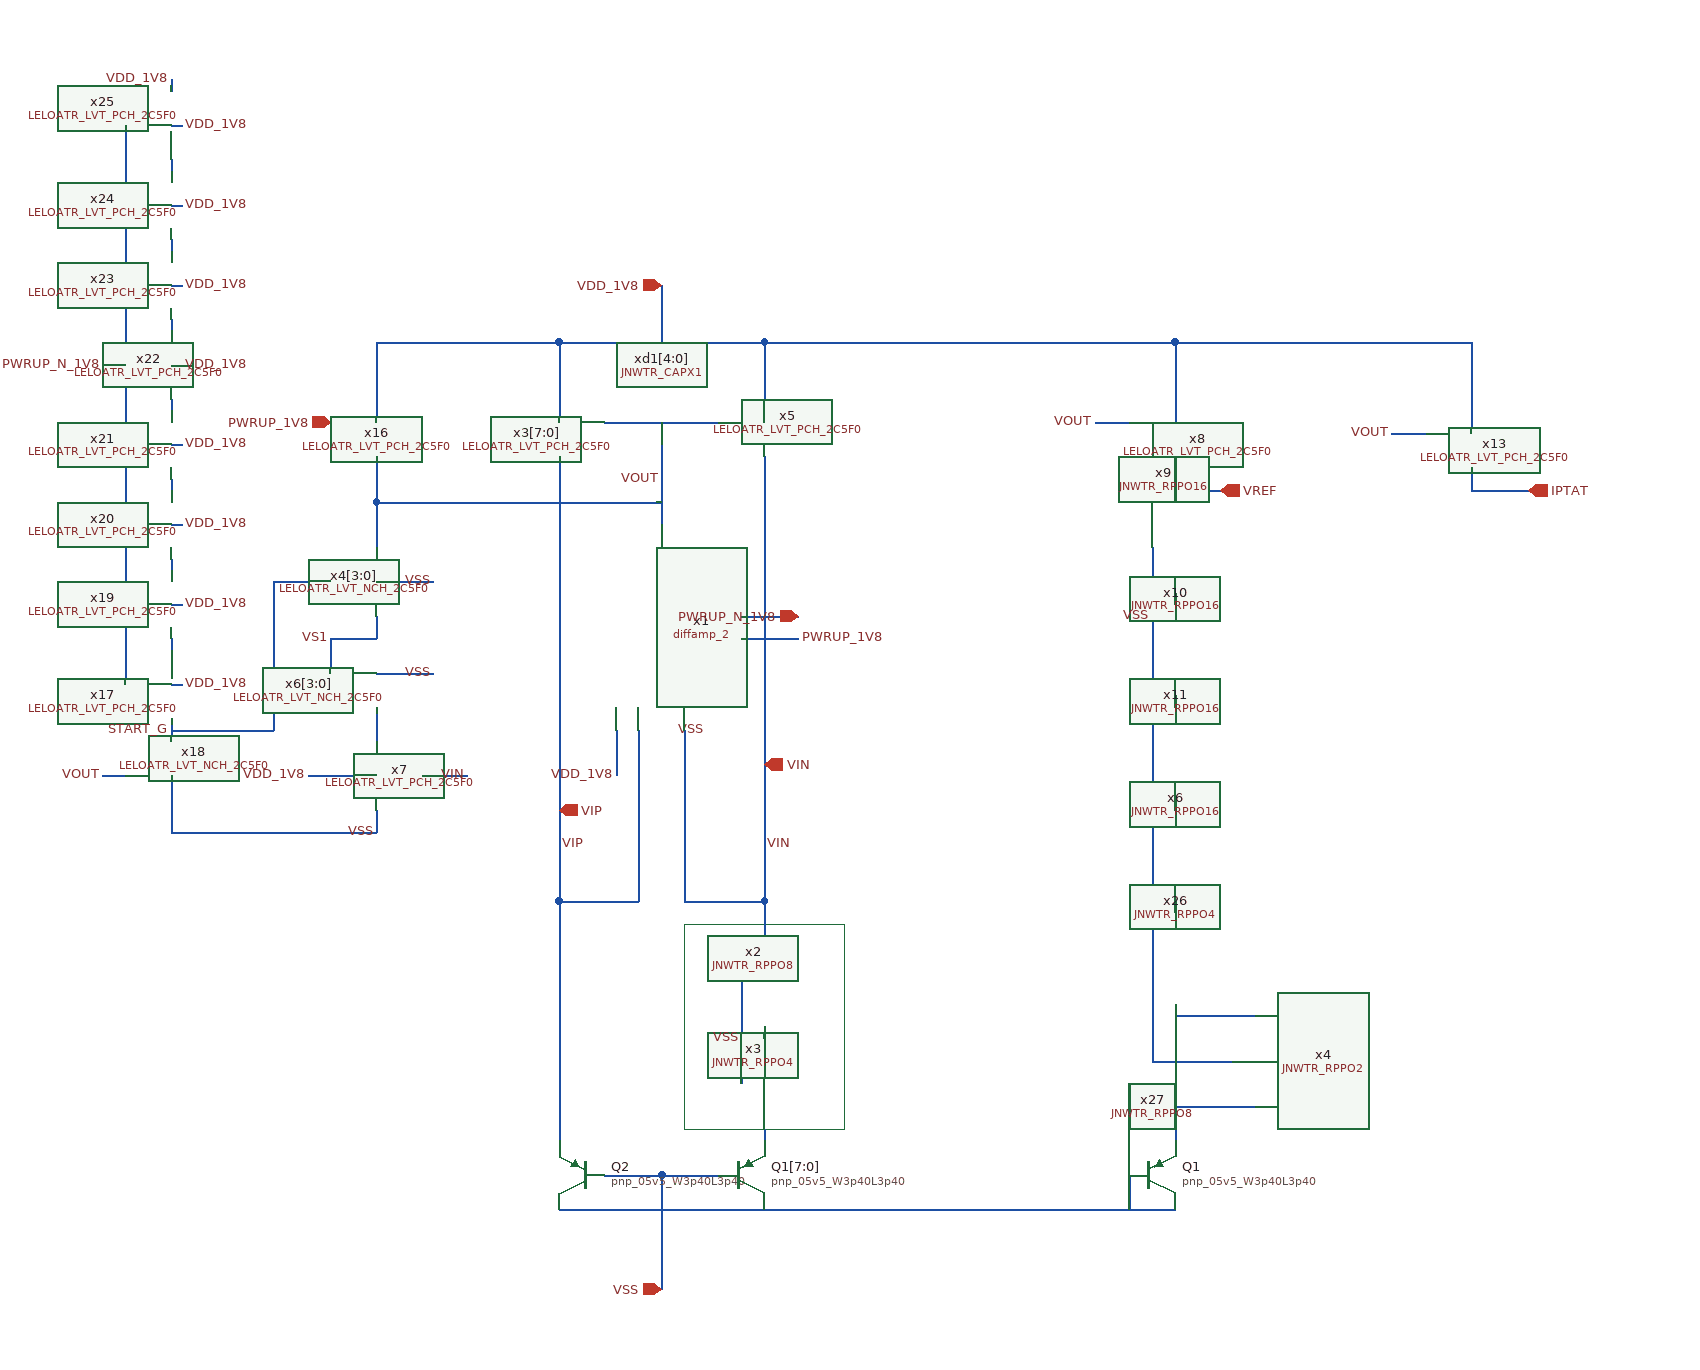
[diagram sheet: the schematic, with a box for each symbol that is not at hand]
v {xschem version=3.4.7 file_version=1.2}
G {}
K {}
V {}
S {}
E {}
L 4 20 440 160 440 {}
L 4 160 440 160 620 {}
L 4 20 620 160 620 {}
L 4 20 440 20 620 {}
P 4 1 60 -60 {}
P 4 1 -130 -150 {}
P 4 1 -80 420 {}
P 4 1 -290 700 {}
P 4 1 -430 420 {}
N 0 0 0 90 {lab=VOUT}
N -90 420 -90 630 {lab=VIP}
N -90 30 -90 420 {lab=VIP}
N -90 -30 -90 0 {lab=VDD_1V8}
N 0 -120 0 -100 {lab=VDD_1V8}
N -90 -50 -90 -30 {lab=VDD_1V8}
N -40 270 -40 310 {lab=VDD_1V8}
N -90 420 -20 420 {lab=VIP}
N 0 730 0 760 {lab=VSS}
N -50 0 50 0 {lab=VOUT}
N 90 -50 90 -30 {lab=VDD_1V8}
N -90 -70 90 -70 {lab=VDD_1V8}
N 90 -70 90 -50 {lab=VDD_1V8}
N -90 -70 -90 -50 {lab=VDD_1V8}
N -0 -100 -0 -70 {lab=VDD_1V8}
N -0 660 -0 730 {lab=VSS}
N -50 690 -0 690 {lab=VSS}
N -0 690 50 690 {lab=VSS}
N 90 420 90 450 {lab=VIN}
N 20 420 90 420 {lab=VIN}
N 70 490 70 580 {lab=VSS}
N 90 530 90 540 {lab=#net1}
N 90 -30 90 -0 {lab=VDD_1V8}
N -250 70 -250 110 {lab=VOUT}
N -250 70 0 70 {lab=VOUT}
N -250 140 -200 140 {lab=VSS}
N -250 220 -200 220 {lab=VSS}
N -250 170 -250 190 {lab=VS1}
N -290 190 -250 190 {lab=VS1}
N -290 190 -290 220 {lab=VS1}
N -210 310 -170 310 {lab=VIN}
N -310 310 -250 310 {lab=VDD_1V8}
N -250 250 -250 280 {lab=#net2}
N -250 340 -250 360 {lab=VSS}
N -50 660 -30 660 {lab=VSS}
N -20 270 -20 330 {lab=VIP}
N 20 270 20 330 {lab=VIN}
N 90 620 90 630 {lab=#net3}
N 90 -70 250 -70 {lab=VDD_1V8}
N 450 -30 450 0 {lab=VDD_1V8}
N 380 0 410 0 {lab=VOUT}
N 450 30 450 60 {lab=VREF}
N 450 60 490 60 {lab=VREF}
N 450 150 450 160 {lab=#net4}
N 450 240 450 250 {lab=#net5}
N 50 690 250 690 {lab=VSS}
N 410 660 410 690 {lab=VSS}
N 430 110 430 290 {lab=VSS}
N 450 330 450 340 {lab=#net6}
N 430 290 430 380 {lab=VSS}
N -20 330 -20 420 {lab=VIP}
N 20 330 20 420 {lab=VIN}
N 90 30 90 70 {lab=VIN}
N 90 70 90 100 {lab=VIN}
N 90 130 90 370 {lab=VIN}
N 90 370 90 420 {lab=VIN}
N 250 -70 440 -70 {lab=VDD_1V8}
N 250 690 450 690 {lab=VSS}
N 450 -70 450 -30 {lab=VDD_1V8}
N 440 -70 450 -70 {lab=VDD_1V8}
N 90 100 90 130 {lab=VIN}
N -90 690 -50 690 {lab=VSS}
N -30 660 -0 660 {lab=VSS}
N 0 660 50 660 {lab=VSS}
N 450 60 450 70 {lab=VREF}
N 450 -70 710 -70 {lab=VDD_1V8}
N 710 -70 710 -20 {lab=VDD_1V8}
N 710 -20 710 10 {lab=VDD_1V8}
N 640 10 670 10 {lab=VOUT}
N 710 40 710 60 {lab=IPTAT}
N 710 60 760 60 {lab=IPTAT}
N 70 190 120 190 {lab=PWRUP_1V8}
N 70 170 120 170 {lab=PWRUP_N_1V8}
N -250 -70 -250 0 {lab=VDD_1V8}
N -250 -70 -90 -70 {lab=VDD_1V8}
N -250 30 -250 70 {lab=VOUT}
N -490 310 -470 310 {lab=VOUT}
N -430 310 -430 340 {lab=VSS}
N -430 340 -430 360 {lab=VSS}
N -430 360 -250 360 {lab=VSS}
N -430 260 -430 280 {lab=START_G}
N -470 -260 -470 230 {lab=PWRUP_N_1V8}
N -490 -50 -470 -50 {lab=PWRUP_N_1V8}
N -430 -300 -430 -290 {lab=VDD_1V8}
N -430 270 -340 270 {lab=START_G}
N -340 140 -340 270 {lab=START_G}
N -340 140 -290 140 {lab=START_G}
N 430 380 430 560 {lab=VSS}
N 450 510 450 520 {lab=#net7}
N 450 420 450 430 {lab=#net8}
N 450 600 450 630 {lab=#net9}
N 430 560 500 560 {lab=VSS}
N 450 600 520 600 {lab=#net9}
N 450 520 520 520 {lab=#net7}
N -430 -90 -430 -80 {lab=#net10}
N -430 -160 -430 -150 {lab=#net11}
N -430 -230 -430 -220 {lab=#net12}
N -430 -20 -430 -10 {lab=#net13}
N -430 50 -430 60 {lab=#net14}
N -430 120 -430 130 {lab=#net15}
N -430 190 -430 200 {lab=#net16}
N -430 230 -420 230 {lab=VDD_1V8}
N -430 160 -420 160 {lab=VDD_1V8}
N -430 90 -420 90 {lab=VDD_1V8}
N -430 20 -420 20 {lab=VDD_1V8}
N -430 -50 -420 -50 {lab=VDD_1V8}
N -430 -120 -420 -120 {lab=VDD_1V8}
N -430 -190 -420 -190 {lab=VDD_1V8}
N -430 -260 -420 -260 {lab=VDD_1V8}
C {devices/lab_wire.sym} -40 310 0 0 {name=p2 sig_type=std_logic lab=VDD_1V8}
C {devices/lab_wire.sym} 40 270 3 0 {name=p6 sig_type=std_logic lab=VSS}
C {devices/ipin.sym} 0 -120 0 0 {name=p7 lab=VDD_1V8}
C {devices/ipin.sym} 0 760 0 0 {name=p11 lab=VSS}
C {LELO_ATR_SKY130A/LELOATR_LVT_PCH_2C5F0.sym} 50 0 0 0 {name=x5}
C {LELO_ATR_SKY130A/LELOATR_LVT_PCH_2C5F0.sym} -50 0 0 1 {name=x3[7:0]}
C {JNW_TR_SKY130A/JNWTR_CAPX1.sym} 0 -60 2 1 {name=xd1[4:0]}
C {sky130_fd_pr/pnp_05v5.sym} -70 660 0 1 {name=Q2
model=pnp_05v5_W3p40L3p40
m=1
spiceprefix=X
}
C {sky130_fd_pr/pnp_05v5.sym} 70 660 0 0 {name=Q1[7:0]
model=pnp_05v5_W3p40L3p40
m=1
spiceprefix=X
}
C {devices/lab_wire.sym} 90 370 2 0 {name=p3 sig_type=std_logic lab=VIN}
C {devices/lab_wire.sym} -90 370 2 0 {name=p5 sig_type=std_logic lab=VIP
}
C {JNW_TR_SKY130A/JNWTR_RPPO8.sym} 90 450 1 0 {name=x2 }
C {JNW_TR_SKY130A/JNWTR_RPPO4.sym} 90 540 1 0 {name=x3 }
C {devices/lab_wire.sym} 70 540 0 0 {name=p14 sig_type=std_logic lab=VSS}
C {LELO_ATR_SKY130A/LELOATR_LVT_NCH_2C5F0.sym} -290 140 0 0 {name=x4[3:0]}
C {LELO_ATR_SKY130A/LELOATR_LVT_NCH_2C5F0.sym} -290 220 0 0 {name=x6[3:0]}
C {devices/lab_wire.sym} -200 140 0 0 {name=p17 sig_type=std_logic lab=VSS}
C {devices/lab_wire.sym} -200 220 0 0 {name=p18 sig_type=std_logic lab=VSS}
C {LELO_ATR_SKY130A/LELOATR_LVT_PCH_2C5F0.sym} -210 310 0 1 {name=x7}
C {devices/lab_wire.sym} -170 310 0 0 {name=p19 sig_type=std_logic lab=VIN
}
C {devices/lab_wire.sym} -310 310 0 0 {name=p20 sig_type=std_logic lab=VDD_1V8}
C {devices/lab_wire.sym} -250 360 0 0 {name=p21 sig_type=std_logic lab=VSS}
C {devices/opin.sym} 760 60 0 0 {name=p23 lab=IPTAT}
C {LELO_ATR_SKY130A/LELOATR_LVT_PCH_2C5F0.sym} 410 0 0 0 {name=x8}
C {devices/lab_wire.sym} 380 0 0 0 {name=p16 sig_type=std_logic lab=VOUT}
C {devices/opin.sym} 490 60 0 0 {name=p24 lab=VREF}
C {JNW_TR_SKY130A/JNWTR_RPPO16.sym} 450 70 1 0 {name=x9}
C {JNW_TR_SKY130A/JNWTR_RPPO16.sym} 450 160 1 0 {name=x10 }
C {JNW_TR_SKY130A/JNWTR_RPPO16.sym} 450 250 1 0 {name=x11 }
C {sky130_fd_pr/pnp_05v5.sym} 430 660 0 0 {name=Q1
model=pnp_05v5_W3p40L3p40
m=1
spiceprefix=X
}
C {devices/lab_wire.sym} 430 170 0 0 {name=p25 sig_type=std_logic lab=VSS}
C {LELO_GR01_SKY130A/diffamp_2.sym} 0 120 3 0 {name=x1}
C {devices/lab_wire.sym} 0 50 0 0 {name=p9 sig_type=std_logic lab=VOUT}
C {devices/lab_wire.sym} -290 190 0 0 {name=p26 sig_type=std_logic lab=VS1}
C {JNW_TR_SKY130A/JNWTR_RPPO16.sym} 450 340 1 0 {name=x6}
C {LELO_ATR_SKY130A/LELOATR_LVT_PCH_2C5F0.sym} 670 10 0 0 {name=x13}
C {devices/lab_wire.sym} 640 10 0 0 {name=p8 sig_type=std_logic lab=VOUT}
C {devices/ipin.sym} -290 0 0 0 {name=p1 lab=PWRUP_1V8}
C {devices/ipin.sym} 120 170 2 0 {name=p13 lab=PWRUP_N_1V8}
C {devices/lab_wire.sym} 120 190 2 0 {name=p15 sig_type=std_logic lab=PWRUP_1V8}
C {LELO_ATR_SKY130A/LELOATR_LVT_PCH_2C5F0.sym} -290 0 0 0 {name=x16}
C {LELO_ATR_SKY130A/LELOATR_LVT_PCH_2C5F0.sym} -470 230 0 0 {name=x17}
C {LELO_ATR_SKY130A/LELOATR_LVT_NCH_2C5F0.sym} -470 310 0 0 {name=x18 }
C {devices/lab_wire.sym} -490 310 0 0 {name=p22 sig_type=std_logic lab=VOUT}
C {LELO_ATR_SKY130A/LELOATR_LVT_PCH_2C5F0.sym} -470 160 0 0 {name=x19}
C {LELO_ATR_SKY130A/LELOATR_LVT_PCH_2C5F0.sym} -470 90 0 0 {name=x20}
C {LELO_ATR_SKY130A/LELOATR_LVT_PCH_2C5F0.sym} -470 20 0 0 {name=x21}
C {LELO_ATR_SKY130A/LELOATR_LVT_PCH_2C5F0.sym} -470 -50 0 0 {name=x22}
C {LELO_ATR_SKY130A/LELOATR_LVT_PCH_2C5F0.sym} -470 -120 0 0 {name=x23}
C {LELO_ATR_SKY130A/LELOATR_LVT_PCH_2C5F0.sym} -470 -190 0 0 {name=x24}
C {LELO_ATR_SKY130A/LELOATR_LVT_PCH_2C5F0.sym} -470 -260 0 0 {name=x25}
C {devices/lab_wire.sym} -430 270 0 0 {name=p27 sig_type=std_logic lab=START_G
}
C {devices/lab_wire.sym} -490 -50 2 1 {name=p28 sig_type=std_logic lab=PWRUP_N_1V8}
C {devices/lab_wire.sym} -430 -300 0 0 {name=p29 sig_type=std_logic lab=VDD_1V8}
C {JNW_TR_SKY130A/JNWTR_RPPO4.sym} 450 430 1 0 {name=x26}
C {JNW_TR_SKY130A/JNWTR_RPPO8.sym} 450 520 1 0 {name=x27}
C {devices/opin.sym} 90 300 0 0 {name=p41 lab=VIN}
C {devices/opin.sym} -90 340 0 0 {name=p42 lab=VIP}
C {JNW_TR_SKY130A/JNWTR_RPPO2.sym} 520 520 1 0 {name=x4}
C {devices/lab_wire.sym} -420 230 0 1 {name=p4 sig_type=std_logic lab=VDD_1V8}
C {devices/lab_wire.sym} -420 160 0 1 {name=p10 sig_type=std_logic lab=VDD_1V8}
C {devices/lab_wire.sym} -420 90 0 1 {name=p12 sig_type=std_logic lab=VDD_1V8}
C {devices/lab_wire.sym} -420 20 0 1 {name=p30 sig_type=std_logic lab=VDD_1V8}
C {devices/lab_wire.sym} -420 -50 0 1 {name=p31 sig_type=std_logic lab=VDD_1V8}
C {devices/lab_wire.sym} -420 -120 0 1 {name=p32 sig_type=std_logic lab=VDD_1V8}
C {devices/lab_wire.sym} -420 -190 0 1 {name=p33 sig_type=std_logic lab=VDD_1V8}
C {devices/lab_wire.sym} -420 -260 0 1 {name=p34 sig_type=std_logic lab=VDD_1V8}
